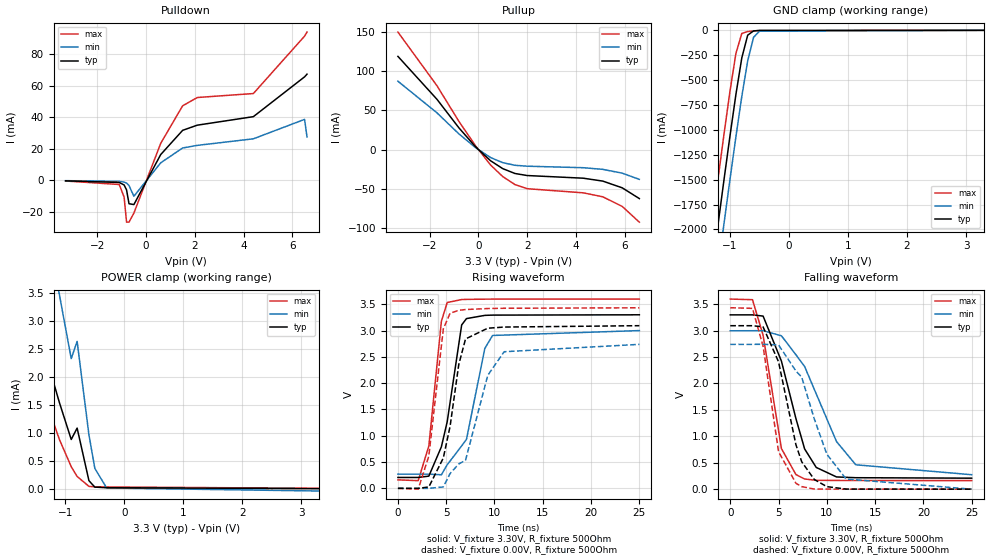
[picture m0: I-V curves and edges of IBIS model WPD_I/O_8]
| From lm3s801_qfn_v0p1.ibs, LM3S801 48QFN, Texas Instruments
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[Model]   WPD_I/O_8
Model_type   I/O
Vinl = 1.26
Vinh = 2.04
Vmeas = 1.65
| variable   typ   min   max
C_comp   9.739pF   9.739pF   9.739pF
[Model Spec]
Vinh+   1.91   1.78   2.04
Vinh-   1.90   1.76   2.03
Vinl+   1.40   1.27   1.54
Vinl-   1.39   1.26   1.53
| variable   typ   min   max
[Temperature Range]  25   85   -40
[Voltage Range]   3.3V   3.0V   3.6V
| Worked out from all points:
|   slope of the pulldown table from 0 to 0.495 V, typ, clamps not added: 35.8 ohm
|   slope of the pullup table from 0 to 0.495 V, typ, clamps not added: 35.8 ohm
|   GND clamp passes 1 mA (typ) near -0.48 V on its own axis
|   POWER clamp passes 1 mA (typ) near -0.79 V on its own axis
|   falling waveform, V_fixture 3.30V, R_fixture 500Ohm: 20-80 % time 2.57ns typ, 3.86ns min, 1.79ns max; typ from 3.3 V to 0.208 V
|   rising waveform, V_fixture 3.30V, R_fixture 500Ohm: 20-80 % time 1.44ns typ, 2.06ns min, 1.12ns max; typ from 0.208 V to 3.3 V
|   falling waveform, V_fixture 0.00V, R_fixture 500Ohm: 20-80 % time 2.33ns typ, 3.18ns min, 1.71ns max; typ from 3.09 V to 0 V
|   rising waveform, V_fixture 0.00V, R_fixture 500Ohm: 20-80 % time 1.63ns typ, 2.35ns min, 1.21ns max; typ from 0 V to 3.09 V
[Pulldown]
|  Voltage   I(typ)   I(min)   I(max)
-3.3V     -256.5uA   -145.6uA   -364.4uA
-1.1V     -1.273mA   -587.4uA   -2.566mA
-900mV    -2.885mA   -1.061mA   -10.54mA
-800mV    -5.992mA   -1.67mA    -26.39mA
-700mV    -14.71mA   -3.214mA   -26.32mA
-500mV    -15.25mA   -9.999mA   -20.65mA
600mV     16.35mA    11.13mA    23.4mA
1.5V      31.67mA    20.51mA    47.18mA
2.1V      34.93mA    22.16mA    52.41mA
4.4V      40.31mA    26.31mA    54.92mA
6.5V      65.47mA    38.59mA    91.21mA
6.6V      67.19mA    27.43mA    93.76mA
[Pullup]
|  Voltage   I(typ)   I(min)   I(max)
-3.3V     118.8mA    87.2mA     149.7mA
-1.7V     64.24mA    47.01mA    81.5mA
-800mV    27.93mA    20.23mA    36.16mA
-100mV    3.223mA    2.35mA     4.341mA
500mV     -13.97mA   -9.848mA   -19.37mA
1V        -24.01mA   -16.38mA   -34.13mA
1.5V      -30.15mA   -19.7mA    -44.24mA
2V        -32.74mA   -20.87mA   -49.48mA
4.3V      -36.12mA   -22.8mA    -54.74mA
5.1V      -39.81mA   -24.88mA   -59.77mA
5.9V      -48.4mA    -29.75mA   -72.06mA
6.6V      -62.06mA   -37.61mA   -92.08mA
[GND Clamp]
|  Voltage   I(typ)   I(min)   I(max)
-3.3V     -11.72A    -12.12A    -11.3A
-1.4V     -2.845A    -3.285A    -2.387A
-1.3V     -2.39A     -2.831A    -1.93A
-1.2V     -1.938A    -2.38A     -1.478A
-1.1V     -1.494A    -1.934A    -1.036A
-1V       -1.059A    -1.496A    -610.6mA
-900mV    -645mA     -1.069A    -232.9mA
-800mV    -277.1mA   -664.4mA   -31.59mA
-700mV    -48.56mA   -306.6mA   -12.1mA
-600mV    -5.561mA   -70.2mA    -6.281mA
-500mV    -1.172mA   -7.88mA    -2.176mA
3.3V      16.11uA    11.84uA    29.77uA
[POWER Clamp]
|  Voltage   I(typ)   I(min)   I(max)
-3.3V     12.42mA    17.27mA    12.25mA
-1.9V     4.935mA    8.337mA    4.102mA
-1.8V     4.461mA    7.714mA    3.616mA
-1.6V     3.549mA    6.478mA    2.703mA
-1.2V     1.906mA    4.063mA    1.182mA
-1.1V     1.542mA    3.476mA    880.4uA
-900mV    882uA      2.332mA    394.1uA
-800mV    1.086mA    2.641mA    218.2uA
-600mV    142.8uA    965.1uA    40.85uA
-500mV    27.22uA    363.6uA    30.71uA
-300mV    16.12uA    11.84uA    29.79uA
3.3V      -104.7pA   -42.65uA   5.692uA
[Ramp]
| variable   typ   min   max
dV/dt_f   1.85/2.57n   1.63/3.86n   2.06/1.79n
dV/dt_r   1.86/1.63n   1.64/2.35n   2.06/1.21n
R_load = 500Ohm
[Falling Waveform]
V_fixture = 3.30V
V_fixture_min = 3.00V
V_fixture_max = 3.60V
R_fixture = 500Ohm
|   Time   V(typ)   V(min)   V(max)
0s        3.298V     2.997V     3.597V
2.3ns     3.298V     2.998V     3.585V
3.4ns     3.275V     2.999V     2.913V
5.3ns     2.422V     2.902V     767.5mV
6.8ns     1.336V     2.543V     276mV
7.7ns     761.6mV    2.321V     192.4mV
8.9ns     411.4mV    1.804V     167.9mV
11ns      231.4mV    900.8mV    164.8mV
13ns      216.8mV    461.3mV    163.7mV
25ns      208.1mV    273.3mV    162.3mV
[Rising Waveform]
V_fixture = 3.30V
V_fixture_min = 3.00V
V_fixture_max = 3.60V
R_fixture = 500Ohm
|   Time   V(typ)   V(min)   V(max)
0s        207.6mV    270.9mV    162.2mV
2.1ns     207.5mV    270.3mV    146.4mV
3.2ns     232.7mV    270mV      806.4mV
4.5ns     789.7mV    258.8mV    3.175V
5.1ns     1.264V     448.4mV    3.532V
6.6ns     3.106V     806.8mV    3.589V
7.1ns     3.227V     933.4mV    3.592V
9ns       3.288V     2.661V     3.596V
9.8ns     3.293V     2.906V     3.597V
25ns      3.299V     2.999V     3.598V
[Falling Waveform]
V_fixture = 0.00V
V_fixture_min = 0.00V
V_fixture_max = 0.00V
R_fixture = 500Ohm
|   Time   V(typ)   V(min)   V(max)
0s        3.093V     2.74V      3.433V
2.3ns     3.093V     2.74V      3.421V
3.4ns     3.071V     2.741V     2.703V
5ns       2.41V      2.729V     709.8mV
6.8ns     840.5mV    2.236V     111.3mV
7.4ns     517.6mV    2.119V     48.34mV
8.7ns     183.6mV    1.33V      2.396mV
10ns      47.84mV    661.3mV    971.6uV
12ns      1.859mV    192.2mV    80.43uV
25ns      33.76uV    46.94uV    17.16uV
[Rising Waveform]
V_fixture = 0.00V
V_fixture_min = 0.00V
V_fixture_max = 0.00V
R_fixture = 500Ohm
|   Time   V(typ)   V(min)   V(max)
0s        187.3uV    3.045mV    99.43uV
2.1ns     120.3uV    610.3uV    -15.01mV
3.2ns     27.21mV    306.8uV    616.1mV
4.7ns     578.6mV    27.48mV    3.03V
5.4ns     1.178V     281.4mV    3.329V
6.3ns     2.354V     464.6mV    3.384V
7ns       2.84V      532.8mV    3.399V
9.3ns     3.044V     2.148V     3.418V
11ns      3.066V     2.597V     3.423V
25ns      3.092V     2.737V     3.432V
